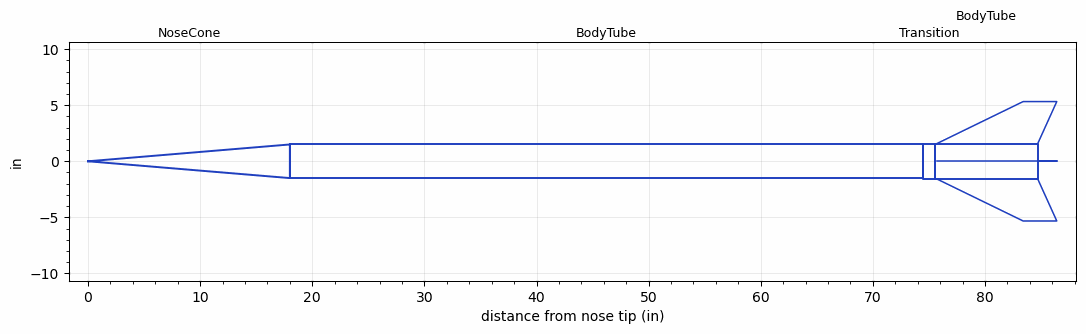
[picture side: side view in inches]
<RASAeroDocument>
 <FileVersion>2</FileVersion>
 <RocketDesign>
  <NoseCone>
   <Length>18</Length>
   <Diameter>3</Diameter>
   <Shape>Conical</Shape>
   <BluntRadius>0.065</BluntRadius>
   <Location>0</Location>
  </NoseCone>
  <BodyTube>
   <Length>56.4999</Length>
   <Diameter>3</Diameter>
   <Location>18</Location>
  </BodyTube>
  <Transition>
   <Length>1</Length>
   <Diameter>3.15</Diameter>
   <Location>74.4999</Location>
   <RearDiameter>3.15</RearDiameter>
  </Transition>
  <BodyTube>
   <Length>9.2</Length>
   <Diameter>3.15</Diameter>
   <Location>75.4999</Location>
   <Fin>
    <Count>4</Count>
    <Chord>9</Chord>
    <Span>3.75</Span>
    <SweepDistance>7.7</SweepDistance>
    <TipChord>3</TipChord>
    <Thickness>0.2</Thickness>
    <LERadius>0.024</LERadius>
    <Location>9</Location>
    <AirfoilSection>Hexagonal</AirfoilSection>
    <FX1>1</FX1>
    <FX3>0.5</FX3>
   </Fin>
  </BodyTube>
  <Surface>Smooth Paint</Surface>
  <ModifiedBarrowman>True</ModifiedBarrowman>
  <Turbulence>True</Turbulence>
  <UseBooster1>False</UseBooster1>
  <UseBooster2>False</UseBooster2>
 </RocketDesign>
 <LaunchSite>
  <Altitude>2000</Altitude>
  <Pressure>27.8281</Pressure>
  <RodAngle>0</RodAngle>
  <RodLength>3.2808</RodLength>
  <Temperature>51.8677</Temperature>
  <WindSpeed>4.4739</WindSpeed>
 </LaunchSite>
 <Recovery>
  <Altitude1>0</Altitude1>
  <Altitude2>0</Altitude2>
  <DeviceType1>None</DeviceType1>
  <DeviceType2>None</DeviceType2>
  <Event1>False</Event1>
  <Event2>False</Event2>
  <Size1>0</Size1>
  <Size2>0</Size2>
  <EventType1>None</EventType1>
  <EventType2>None</EventType2>
  <CD1>0</CD1>
  <CD2>0</CD2>
 </Recovery>
 <SimulationList>
  <Simulation>
   <SustainerEngine>N3505TF  (Walter)</SustainerEngine>
   <SustainerLaunchWt>30.7</SustainerLaunchWt>
   <SustainerCG>50.8</SustainerCG>
   <SustainerIgnitionDelay>0</SustainerIgnitionDelay>
   <Booster1SeparationDelay>0</Booster1SeparationDelay>
   <Booster1IgnitionDelay>0</Booster1IgnitionDelay>
   <IncludeBooster1>False</IncludeBooster1>
   <Booster2Delay>0</Booster2Delay>
   <IncludeBooster2>False</IncludeBooster2>
   <TimetoApogee>55.01677</TimetoApogee>
   <MaxAltitude>64637.91</MaxAltitude>
   <MaxVelocity>3965.201</MaxVelocity>
  </Simulation>
  <Simulation>
   <SustainerLaunchWt>2.5</SustainerLaunchWt>
   <SustainerCG>43.0857</SustainerCG>
   <SustainerIgnitionDelay>0</SustainerIgnitionDelay>
   <Booster1SeparationDelay>0</Booster1SeparationDelay>
   <Booster1IgnitionDelay>0</Booster1IgnitionDelay>
   <IncludeBooster1>False</IncludeBooster1>
   <Booster2Delay>0</Booster2Delay>
   <IncludeBooster2>False</IncludeBooster2>
  </Simulation>
  <Simulation>
   <SustainerLaunchWt>2.5</SustainerLaunchWt>
   <SustainerCG>43.0857</SustainerCG>
   <SustainerIgnitionDelay>0</SustainerIgnitionDelay>
   <Booster1SeparationDelay>0</Booster1SeparationDelay>
   <Booster1IgnitionDelay>0</Booster1IgnitionDelay>
   <IncludeBooster1>False</IncludeBooster1>
   <Booster2Delay>0</Booster2Delay>
   <IncludeBooster2>False</IncludeBooster2>
  </Simulation>
  <Simulation>
   <SustainerLaunchWt>2.5</SustainerLaunchWt>
   <SustainerCG>43.0857</SustainerCG>
   <SustainerIgnitionDelay>0</SustainerIgnitionDelay>
   <Booster1SeparationDelay>0</Booster1SeparationDelay>
   <Booster1IgnitionDelay>0</Booster1IgnitionDelay>
   <IncludeBooster1>False</IncludeBooster1>
   <Booster2Delay>0</Booster2Delay>
   <IncludeBooster2>False</IncludeBooster2>
  </Simulation>
  <Simulation>
   <SustainerLaunchWt>2.5</SustainerLaunchWt>
   <SustainerCG>43.0857</SustainerCG>
   <SustainerIgnitionDelay>0</SustainerIgnitionDelay>
   <Booster1SeparationDelay>0</Booster1SeparationDelay>
   <Booster1IgnitionDelay>0</Booster1IgnitionDelay>
   <IncludeBooster1>False</IncludeBooster1>
   <Booster2Delay>0</Booster2Delay>
   <IncludeBooster2>False</IncludeBooster2>
  </Simulation>
  <Simulation>
   <SustainerLaunchWt>2.5</SustainerLaunchWt>
   <SustainerCG>43.0857</SustainerCG>
   <SustainerIgnitionDelay>0</SustainerIgnitionDelay>
   <Booster1SeparationDelay>0</Booster1SeparationDelay>
   <Booster1IgnitionDelay>0</Booster1IgnitionDelay>
   <IncludeBooster1>False</IncludeBooster1>
   <Booster2Delay>0</Booster2Delay>
   <IncludeBooster2>False</IncludeBooster2>
  </Simulation>
 </SimulationList>
</RASAeroDocument>
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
